VERSION 5.7 ;
  NOWIREEXTENSIONATPIN ON ;
  DIVIDERCHAR "/" ;
  BUSBITCHARS "[]" ;
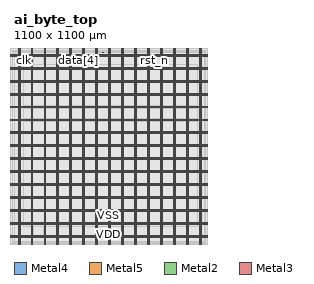
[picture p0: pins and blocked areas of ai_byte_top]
MACRO ai_byte_top
  CLASS BLOCK ;
  FOREIGN ai_byte_top ;
  ORIGIN 0.000 0.000 ;
  SIZE 1100.000 BY 1100.000 ;
  PIN VDD
    DIRECTION INOUT ;
    USE POWER ;
    PORT
      LAYER Metal4 ;
        RECT 23.900 -15.940 28.900 1117.460 ;
    END
    PORT
      LAYER Metal4 ;
        RECT 98.900 -15.940 103.900 1117.460 ;
    END
    PORT
      LAYER Metal4 ;
        RECT 173.900 -15.940 178.900 1117.460 ;
    END
    PORT
      LAYER Metal4 ;
        RECT 248.900 -15.940 253.900 1117.460 ;
    END
    PORT
      LAYER Metal4 ;
        RECT 323.900 -15.940 328.900 1117.460 ;
    END
    PORT
      LAYER Metal4 ;
        RECT 398.900 -15.940 403.900 1117.460 ;
    END
    PORT
      LAYER Metal4 ;
        RECT 473.900 -15.940 478.900 1117.460 ;
    END
    PORT
      LAYER Metal4 ;
        RECT 548.900 -15.940 553.900 1117.460 ;
    END
    PORT
      LAYER Metal4 ;
        RECT 623.900 -15.940 628.900 1117.460 ;
    END
    PORT
      LAYER Metal4 ;
        RECT 698.900 -15.940 703.900 1117.460 ;
    END
    PORT
      LAYER Metal4 ;
        RECT 773.900 -15.940 778.900 1117.460 ;
    END
    PORT
      LAYER Metal4 ;
        RECT 848.900 -15.940 853.900 1117.460 ;
    END
    PORT
      LAYER Metal4 ;
        RECT 923.900 -15.940 928.900 1117.460 ;
    END
    PORT
      LAYER Metal4 ;
        RECT 998.900 -15.940 1003.900 1117.460 ;
    END
    PORT
      LAYER Metal4 ;
        RECT 1073.900 -15.940 1078.900 1117.460 ;
    END
    PORT
      LAYER Metal5 ;
        RECT -17.620 25.910 1117.460 30.910 ;
    END
    PORT
      LAYER Metal5 ;
        RECT -17.620 100.910 1117.460 105.910 ;
    END
    PORT
      LAYER Metal5 ;
        RECT -17.620 175.910 1117.460 180.910 ;
    END
    PORT
      LAYER Metal5 ;
        RECT -17.620 250.910 1117.460 255.910 ;
    END
    PORT
      LAYER Metal5 ;
        RECT -17.620 325.910 1117.460 330.910 ;
    END
    PORT
      LAYER Metal5 ;
        RECT -17.620 400.910 1117.460 405.910 ;
    END
    PORT
      LAYER Metal5 ;
        RECT -17.620 475.910 1117.460 480.910 ;
    END
    PORT
      LAYER Metal5 ;
        RECT -17.620 550.910 1117.460 555.910 ;
    END
    PORT
      LAYER Metal5 ;
        RECT -17.620 625.910 1117.460 630.910 ;
    END
    PORT
      LAYER Metal5 ;
        RECT -17.620 700.910 1117.460 705.910 ;
    END
    PORT
      LAYER Metal5 ;
        RECT -17.620 775.910 1117.460 780.910 ;
    END
    PORT
      LAYER Metal5 ;
        RECT -17.620 850.910 1117.460 855.910 ;
    END
    PORT
      LAYER Metal5 ;
        RECT -17.620 925.910 1117.460 930.910 ;
    END
    PORT
      LAYER Metal5 ;
        RECT -17.620 1000.910 1117.460 1005.910 ;
    END
    PORT
      LAYER Metal5 ;
        RECT -17.620 1075.910 1117.460 1080.910 ;
    END
  END VDD
  PIN VSS
    DIRECTION INOUT ;
    USE GROUND ;
    PORT
      LAYER Metal4 ;
        RECT 29.900 -15.940 34.900 1117.460 ;
    END
    PORT
      LAYER Metal4 ;
        RECT 104.900 -15.940 109.900 1117.460 ;
    END
    PORT
      LAYER Metal4 ;
        RECT 179.900 -15.940 184.900 1117.460 ;
    END
    PORT
      LAYER Metal4 ;
        RECT 254.900 -15.940 259.900 1117.460 ;
    END
    PORT
      LAYER Metal4 ;
        RECT 329.900 -15.940 334.900 1117.460 ;
    END
    PORT
      LAYER Metal4 ;
        RECT 404.900 -15.940 409.900 1117.460 ;
    END
    PORT
      LAYER Metal4 ;
        RECT 479.900 -15.940 484.900 1117.460 ;
    END
    PORT
      LAYER Metal4 ;
        RECT 554.900 -15.940 559.900 1117.460 ;
    END
    PORT
      LAYER Metal4 ;
        RECT 629.900 -15.940 634.900 1117.460 ;
    END
    PORT
      LAYER Metal4 ;
        RECT 704.900 -15.940 709.900 1117.460 ;
    END
    PORT
      LAYER Metal4 ;
        RECT 779.900 -15.940 784.900 1117.460 ;
    END
    PORT
      LAYER Metal4 ;
        RECT 854.900 -15.940 859.900 1117.460 ;
    END
    PORT
      LAYER Metal4 ;
        RECT 929.900 -15.940 934.900 1117.460 ;
    END
    PORT
      LAYER Metal4 ;
        RECT 1004.900 -15.940 1009.900 1117.460 ;
    END
    PORT
      LAYER Metal4 ;
        RECT 1079.900 -15.940 1084.900 1117.460 ;
    END
    PORT
      LAYER Metal5 ;
        RECT -17.620 31.910 1117.460 36.910 ;
    END
    PORT
      LAYER Metal5 ;
        RECT -17.620 106.910 1117.460 111.910 ;
    END
    PORT
      LAYER Metal5 ;
        RECT -17.620 181.910 1117.460 186.910 ;
    END
    PORT
      LAYER Metal5 ;
        RECT -17.620 256.910 1117.460 261.910 ;
    END
    PORT
      LAYER Metal5 ;
        RECT -17.620 331.910 1117.460 336.910 ;
    END
    PORT
      LAYER Metal5 ;
        RECT -17.620 406.910 1117.460 411.910 ;
    END
    PORT
      LAYER Metal5 ;
        RECT -17.620 481.910 1117.460 486.910 ;
    END
    PORT
      LAYER Metal5 ;
        RECT -17.620 556.910 1117.460 561.910 ;
    END
    PORT
      LAYER Metal5 ;
        RECT -17.620 631.910 1117.460 636.910 ;
    END
    PORT
      LAYER Metal5 ;
        RECT -17.620 706.910 1117.460 711.910 ;
    END
    PORT
      LAYER Metal5 ;
        RECT -17.620 781.910 1117.460 786.910 ;
    END
    PORT
      LAYER Metal5 ;
        RECT -17.620 856.910 1117.460 861.910 ;
    END
    PORT
      LAYER Metal5 ;
        RECT -17.620 931.910 1117.460 936.910 ;
    END
    PORT
      LAYER Metal5 ;
        RECT -17.620 1006.910 1117.460 1011.910 ;
    END
    PORT
      LAYER Metal5 ;
        RECT -17.620 1081.910 1117.460 1086.910 ;
    END
  END VSS
  PIN addr[0]
    DIRECTION INPUT ;
    USE SIGNAL ;
    ANTENNAGATEAREA 0.396000 ;
    PORT
      LAYER Metal2 ;
        RECT 427.840 1099.440 428.400 1100.000 ;
    END
  END addr[0]
  PIN addr[1]
    DIRECTION INPUT ;
    USE SIGNAL ;
    ANTENNAGATEAREA 0.396000 ;
    PORT
      LAYER Metal2 ;
        RECT 430.080 1099.440 430.640 1100.000 ;
    END
  END addr[1]
  PIN addr[2]
    DIRECTION INPUT ;
    USE SIGNAL ;
    ANTENNAGATEAREA 0.396000 ;
    PORT
      LAYER Metal2 ;
        RECT 448.000 1099.440 448.560 1100.000 ;
    END
  END addr[2]
  PIN addr[3]
    DIRECTION INPUT ;
    USE SIGNAL ;
    ANTENNAGATEAREA 0.396000 ;
    PORT
      LAYER Metal2 ;
        RECT 450.240 1099.440 450.800 1100.000 ;
    END
  END addr[3]
  PIN clk
    DIRECTION INPUT ;
    USE SIGNAL ;
    ANTENNAGATEAREA 4.738000 ;
    PORT
      LAYER Metal3 ;
        RECT 0.000 1083.040 0.560 1083.600 ;
    END
  END clk
  PIN data[0]
    DIRECTION INOUT ;
    USE SIGNAL ;
    PORT
      LAYER Metal2 ;
        RECT 376.320 1099.440 376.880 1100.000 ;
    END
  END data[0]
  PIN data[1]
    DIRECTION INOUT ;
    USE SIGNAL ;
    ANTENNAGATEAREA 0.396000 ;
    ANTENNADIFFAREA 2.080400 ;
    PORT
      LAYER Metal2 ;
        RECT 393.120 1099.440 393.680 1100.000 ;
    END
  END data[1]
  PIN data[2]
    DIRECTION INOUT ;
    USE SIGNAL ;
    PORT
      LAYER Metal2 ;
        RECT 395.360 1099.440 395.920 1100.000 ;
    END
  END data[2]
  PIN data[3]
    DIRECTION INOUT ;
    USE SIGNAL ;
    ANTENNAGATEAREA 1.057000 ;
    ANTENNADIFFAREA 2.080400 ;
    PORT
      LAYER Metal2 ;
        RECT 396.480 1099.440 397.040 1100.000 ;
    END
  END data[3]
  PIN data[4]
    DIRECTION INOUT ;
    USE SIGNAL ;
    ANTENNADIFFAREA 1.986000 ;
    PORT
      LAYER Metal2 ;
        RECT 370.720 1099.440 371.280 1100.000 ;
    END
  END data[4]
  PIN data[5]
    DIRECTION INOUT ;
    USE SIGNAL ;
    ANTENNAGATEAREA 1.057000 ;
    ANTENNADIFFAREA 0.897600 ;
    PORT
      LAYER Metal2 ;
        RECT 336.000 1099.440 336.560 1100.000 ;
    END
  END data[5]
  PIN data[6]
    DIRECTION INOUT ;
    USE SIGNAL ;
    ANTENNAGATEAREA 1.057000 ;
    ANTENNADIFFAREA 0.897600 ;
    PORT
      LAYER Metal2 ;
        RECT 343.840 1099.440 344.400 1100.000 ;
    END
  END data[6]
  PIN data[7]
    DIRECTION INOUT ;
    USE SIGNAL ;
    ANTENNAGATEAREA 0.396000 ;
    ANTENNADIFFAREA 0.897600 ;
    PORT
      LAYER Metal2 ;
        RECT 329.280 1099.440 329.840 1100.000 ;
    END
  END data[7]
  PIN debug_state[0]
    DIRECTION OUTPUT ;
    USE SIGNAL ;
    ANTENNADIFFAREA 0.897600 ;
    PORT
      LAYER Metal2 ;
        RECT 515.200 1099.440 515.760 1100.000 ;
    END
  END debug_state[0]
  PIN debug_state[1]
    DIRECTION OUTPUT ;
    USE SIGNAL ;
    ANTENNADIFFAREA 0.897600 ;
    PORT
      LAYER Metal2 ;
        RECT 529.760 1099.440 530.320 1100.000 ;
    END
  END debug_state[1]
  PIN debug_state[2]
    DIRECTION OUTPUT ;
    USE SIGNAL ;
    ANTENNADIFFAREA 0.897600 ;
    PORT
      LAYER Metal2 ;
        RECT 528.640 1099.440 529.200 1100.000 ;
    END
  END debug_state[2]
  PIN done_o
    DIRECTION OUTPUT ;
    USE SIGNAL ;
    ANTENNADIFFAREA 0.897600 ;
    PORT
      LAYER Metal2 ;
        RECT 514.080 1099.440 514.640 1100.000 ;
    END
  END done_o
  PIN error_o
    DIRECTION OUTPUT ;
    USE SIGNAL ;
    ANTENNADIFFAREA 0.897600 ;
    PORT
      LAYER Metal2 ;
        RECT 499.520 1099.440 500.080 1100.000 ;
    END
  END error_o
  PIN irq
    DIRECTION OUTPUT ;
    USE SIGNAL ;
    ANTENNADIFFAREA 0.897600 ;
    PORT
      LAYER Metal2 ;
        RECT 484.960 1099.440 485.520 1100.000 ;
    END
  END irq
  PIN re
    DIRECTION INPUT ;
    USE SIGNAL ;
    ANTENNAGATEAREA 0.396000 ;
    PORT
      LAYER Metal2 ;
        RECT 512.960 1099.440 513.520 1100.000 ;
    END
  END re
  PIN rst_n
    DIRECTION INPUT ;
    USE SIGNAL ;
    ANTENNAGATEAREA 0.396000 ;
    PORT
      LAYER Metal2 ;
        RECT 815.360 1099.440 815.920 1100.000 ;
    END
  END rst_n
  PIN we
    DIRECTION INPUT ;
    USE SIGNAL ;
    ANTENNAGATEAREA 0.396000 ;
    PORT
      LAYER Metal2 ;
        RECT 549.920 1099.440 550.480 1100.000 ;
    END
  END we
  OBS
      LAYER Nwell ;
        RECT 9.650 11.330 1090.190 1094.110 ;
      LAYER Metal1 ;
        RECT 10.080 11.460 1089.760 1093.980 ;
      LAYER Metal2 ;
        RECT -17.620 -15.940 -7.620 1117.460 ;
        RECT -5.920 1100.000 4.080 1105.760 ;
        RECT 1095.760 1100.000 1105.760 1105.760 ;
        RECT -5.920 1099.140 328.980 1100.000 ;
        RECT 330.140 1099.140 335.700 1100.000 ;
        RECT 336.860 1099.140 343.540 1100.000 ;
        RECT 344.700 1099.140 370.420 1100.000 ;
        RECT 371.580 1099.140 376.020 1100.000 ;
        RECT 377.180 1099.140 392.820 1100.000 ;
        RECT 393.980 1099.140 395.060 1100.000 ;
        RECT 397.340 1099.140 427.540 1100.000 ;
        RECT 428.700 1099.140 429.780 1100.000 ;
        RECT 430.940 1099.140 447.700 1100.000 ;
        RECT 448.860 1099.140 449.940 1100.000 ;
        RECT 451.100 1099.140 484.660 1100.000 ;
        RECT 485.820 1099.140 499.220 1100.000 ;
        RECT 500.380 1099.140 512.660 1100.000 ;
        RECT 516.060 1099.140 528.340 1100.000 ;
        RECT 530.620 1099.140 549.620 1100.000 ;
        RECT 550.780 1099.140 815.060 1100.000 ;
        RECT 816.220 1099.140 1105.760 1100.000 ;
        RECT -5.920 0.000 1105.760 1099.140 ;
        RECT -5.920 -4.240 4.080 0.000 ;
        RECT 1095.760 -4.240 1105.760 0.000 ;
        RECT 1107.460 -15.940 1117.460 1117.460 ;
      LAYER Metal3 ;
        RECT -17.620 1107.460 1117.460 1117.460 ;
        RECT -5.920 1095.760 1105.760 1105.760 ;
        RECT -17.460 1082.100 -7.780 1086.720 ;
        RECT 0.000 1083.900 1100.000 1095.760 ;
        RECT 0.860 1082.740 1100.000 1083.900 ;
        RECT 0.000 1080.720 1100.000 1082.740 ;
        RECT 1107.620 1082.100 1117.300 1086.720 ;
        RECT -5.760 1076.100 1105.600 1080.720 ;
        RECT -17.460 1007.100 -7.780 1011.720 ;
        RECT 0.000 1005.720 1100.000 1076.100 ;
        RECT 1107.620 1007.100 1117.300 1011.720 ;
        RECT -5.760 1001.100 1105.600 1005.720 ;
        RECT -17.460 932.100 -7.780 936.720 ;
        RECT 0.000 930.720 1100.000 1001.100 ;
        RECT 1107.620 932.100 1117.300 936.720 ;
        RECT -5.760 926.100 1105.600 930.720 ;
        RECT -17.460 857.100 -7.780 861.720 ;
        RECT 0.000 855.720 1100.000 926.100 ;
        RECT 1107.620 857.100 1117.300 861.720 ;
        RECT -5.760 851.100 1105.600 855.720 ;
        RECT -17.460 782.100 -7.780 786.720 ;
        RECT 0.000 780.720 1100.000 851.100 ;
        RECT 1107.620 782.100 1117.300 786.720 ;
        RECT -5.760 776.100 1105.600 780.720 ;
        RECT -17.460 707.100 -7.780 711.720 ;
        RECT 0.000 705.720 1100.000 776.100 ;
        RECT 1107.620 707.100 1117.300 711.720 ;
        RECT -5.760 701.100 1105.600 705.720 ;
        RECT -17.460 632.100 -7.780 636.720 ;
        RECT 0.000 630.720 1100.000 701.100 ;
        RECT 1107.620 632.100 1117.300 636.720 ;
        RECT -5.760 626.100 1105.600 630.720 ;
        RECT -17.460 557.100 -7.780 561.720 ;
        RECT 0.000 555.720 1100.000 626.100 ;
        RECT 1107.620 557.100 1117.300 561.720 ;
        RECT -5.760 551.100 1105.600 555.720 ;
        RECT -17.460 482.100 -7.780 486.720 ;
        RECT 0.000 480.720 1100.000 551.100 ;
        RECT 1107.620 482.100 1117.300 486.720 ;
        RECT -5.760 476.100 1105.600 480.720 ;
        RECT -17.460 407.100 -7.780 411.720 ;
        RECT 0.000 405.720 1100.000 476.100 ;
        RECT 1107.620 407.100 1117.300 411.720 ;
        RECT -5.760 401.100 1105.600 405.720 ;
        RECT -17.460 332.100 -7.780 336.720 ;
        RECT 0.000 330.720 1100.000 401.100 ;
        RECT 1107.620 332.100 1117.300 336.720 ;
        RECT -5.760 326.100 1105.600 330.720 ;
        RECT -17.460 257.100 -7.780 261.720 ;
        RECT 0.000 255.720 1100.000 326.100 ;
        RECT 1107.620 257.100 1117.300 261.720 ;
        RECT -5.760 251.100 1105.600 255.720 ;
        RECT -17.460 182.100 -7.780 186.720 ;
        RECT 0.000 180.720 1100.000 251.100 ;
        RECT 1107.620 182.100 1117.300 186.720 ;
        RECT -5.760 176.100 1105.600 180.720 ;
        RECT -17.460 107.100 -7.780 111.720 ;
        RECT 0.000 105.720 1100.000 176.100 ;
        RECT 1107.620 107.100 1117.300 111.720 ;
        RECT -5.760 101.100 1105.600 105.720 ;
        RECT -17.460 32.100 -7.780 36.720 ;
        RECT 0.000 30.720 1100.000 101.100 ;
        RECT 1107.620 32.100 1117.300 36.720 ;
        RECT -5.760 26.100 1105.600 30.720 ;
        RECT 0.000 5.760 1100.000 26.100 ;
        RECT -5.920 -4.240 1105.760 5.760 ;
        RECT -17.620 -15.940 1117.460 -5.940 ;
      LAYER Metal4 ;
        RECT -17.410 1082.050 -7.830 1086.770 ;
        RECT 0.000 1080.770 23.600 1086.770 ;
        RECT -5.710 1076.050 23.600 1080.770 ;
        RECT -17.410 1007.050 -7.830 1011.770 ;
        RECT 0.000 1005.770 23.600 1076.050 ;
        RECT -5.710 1001.050 23.600 1005.770 ;
        RECT -17.410 932.050 -7.830 936.770 ;
        RECT 0.000 930.770 23.600 1001.050 ;
        RECT -5.710 926.050 23.600 930.770 ;
        RECT -17.410 857.050 -7.830 861.770 ;
        RECT 0.000 855.770 23.600 926.050 ;
        RECT -5.710 851.050 23.600 855.770 ;
        RECT -17.410 782.050 -7.830 786.770 ;
        RECT 0.000 780.770 23.600 851.050 ;
        RECT -5.710 776.050 23.600 780.770 ;
        RECT -17.410 707.050 -7.830 711.770 ;
        RECT 0.000 705.770 23.600 776.050 ;
        RECT -5.710 701.050 23.600 705.770 ;
        RECT -17.410 632.050 -7.830 636.770 ;
        RECT 0.000 630.770 23.600 701.050 ;
        RECT -5.710 626.050 23.600 630.770 ;
        RECT -17.410 557.050 -7.830 561.770 ;
        RECT 0.000 555.770 23.600 626.050 ;
        RECT -5.710 551.050 23.600 555.770 ;
        RECT -17.410 482.050 -7.830 486.770 ;
        RECT 0.000 480.770 23.600 551.050 ;
        RECT -5.710 476.050 23.600 480.770 ;
        RECT -17.410 407.050 -7.830 411.770 ;
        RECT 0.000 405.770 23.600 476.050 ;
        RECT -5.710 401.050 23.600 405.770 ;
        RECT -17.410 332.050 -7.830 336.770 ;
        RECT 0.000 330.770 23.600 401.050 ;
        RECT -5.710 326.050 23.600 330.770 ;
        RECT -17.410 257.050 -7.830 261.770 ;
        RECT 0.000 255.770 23.600 326.050 ;
        RECT -5.710 251.050 23.600 255.770 ;
        RECT -17.410 182.050 -7.830 186.770 ;
        RECT 0.000 180.770 23.600 251.050 ;
        RECT -5.710 176.050 23.600 180.770 ;
        RECT -17.410 107.050 -7.830 111.770 ;
        RECT 0.000 105.770 23.600 176.050 ;
        RECT -5.710 101.050 23.600 105.770 ;
        RECT -17.410 32.050 -7.830 36.770 ;
        RECT 0.000 30.770 23.600 101.050 ;
        RECT -5.710 26.050 23.600 30.770 ;
        RECT 0.000 25.290 23.600 26.050 ;
        RECT 29.200 25.290 29.600 1086.770 ;
        RECT 35.200 25.290 98.600 1086.770 ;
        RECT 104.200 25.290 104.600 1086.770 ;
        RECT 110.200 25.290 173.600 1086.770 ;
        RECT 179.200 25.290 179.600 1086.770 ;
        RECT 185.200 25.290 248.600 1086.770 ;
        RECT 254.200 25.290 254.600 1086.770 ;
        RECT 260.200 25.290 323.600 1086.770 ;
        RECT 329.200 25.290 329.600 1086.770 ;
        RECT 335.200 25.290 398.600 1086.770 ;
        RECT 404.200 25.290 404.600 1086.770 ;
        RECT 410.200 25.290 473.600 1086.770 ;
        RECT 479.200 25.290 479.600 1086.770 ;
        RECT 485.200 25.290 548.600 1086.770 ;
        RECT 554.200 25.290 554.600 1086.770 ;
        RECT 560.200 25.290 623.600 1086.770 ;
        RECT 629.200 25.290 629.600 1086.770 ;
        RECT 635.200 25.290 698.600 1086.770 ;
        RECT 704.200 25.290 704.600 1086.770 ;
        RECT 710.200 25.290 773.600 1086.770 ;
        RECT 779.200 25.290 779.600 1086.770 ;
        RECT 785.200 25.290 848.600 1086.770 ;
        RECT 854.200 25.290 854.600 1086.770 ;
        RECT 860.200 25.290 923.600 1086.770 ;
        RECT 929.200 25.290 929.600 1086.770 ;
        RECT 935.200 25.290 998.600 1086.770 ;
        RECT 1004.200 25.290 1004.600 1086.770 ;
        RECT 1010.200 25.290 1073.600 1086.770 ;
        RECT 1079.200 25.290 1079.600 1086.770 ;
        RECT 1085.200 1080.770 1100.000 1086.770 ;
        RECT 1107.670 1082.050 1117.250 1086.770 ;
        RECT 1085.200 1076.050 1105.550 1080.770 ;
        RECT 1085.200 1005.770 1100.000 1076.050 ;
        RECT 1107.670 1007.050 1117.250 1011.770 ;
        RECT 1085.200 1001.050 1105.550 1005.770 ;
        RECT 1085.200 930.770 1100.000 1001.050 ;
        RECT 1107.670 932.050 1117.250 936.770 ;
        RECT 1085.200 926.050 1105.550 930.770 ;
        RECT 1085.200 855.770 1100.000 926.050 ;
        RECT 1107.670 857.050 1117.250 861.770 ;
        RECT 1085.200 851.050 1105.550 855.770 ;
        RECT 1085.200 780.770 1100.000 851.050 ;
        RECT 1107.670 782.050 1117.250 786.770 ;
        RECT 1085.200 776.050 1105.550 780.770 ;
        RECT 1085.200 705.770 1100.000 776.050 ;
        RECT 1107.670 707.050 1117.250 711.770 ;
        RECT 1085.200 701.050 1105.550 705.770 ;
        RECT 1085.200 630.770 1100.000 701.050 ;
        RECT 1107.670 632.050 1117.250 636.770 ;
        RECT 1085.200 626.050 1105.550 630.770 ;
        RECT 1085.200 555.770 1100.000 626.050 ;
        RECT 1107.670 557.050 1117.250 561.770 ;
        RECT 1085.200 551.050 1105.550 555.770 ;
        RECT 1085.200 480.770 1100.000 551.050 ;
        RECT 1107.670 482.050 1117.250 486.770 ;
        RECT 1085.200 476.050 1105.550 480.770 ;
        RECT 1085.200 405.770 1100.000 476.050 ;
        RECT 1107.670 407.050 1117.250 411.770 ;
        RECT 1085.200 401.050 1105.550 405.770 ;
        RECT 1085.200 330.770 1100.000 401.050 ;
        RECT 1107.670 332.050 1117.250 336.770 ;
        RECT 1085.200 326.050 1105.550 330.770 ;
        RECT 1085.200 255.770 1100.000 326.050 ;
        RECT 1107.670 257.050 1117.250 261.770 ;
        RECT 1085.200 251.050 1105.550 255.770 ;
        RECT 1085.200 180.770 1100.000 251.050 ;
        RECT 1107.670 182.050 1117.250 186.770 ;
        RECT 1085.200 176.050 1105.550 180.770 ;
        RECT 1085.200 105.770 1100.000 176.050 ;
        RECT 1107.670 107.050 1117.250 111.770 ;
        RECT 1085.200 101.050 1105.550 105.770 ;
        RECT 1085.200 30.770 1100.000 101.050 ;
        RECT 1107.670 32.050 1117.250 36.770 ;
        RECT 1085.200 26.050 1105.550 30.770 ;
        RECT 1085.200 25.290 1100.000 26.050 ;
      LAYER Metal5 ;
        RECT 57.740 1012.510 1065.060 1024.870 ;
        RECT 57.740 937.510 1065.060 1000.310 ;
        RECT 57.740 862.510 1065.060 925.310 ;
        RECT 57.740 787.510 1065.060 850.310 ;
        RECT 57.740 712.510 1065.060 775.310 ;
        RECT 57.740 637.510 1065.060 700.310 ;
        RECT 57.740 562.510 1065.060 625.310 ;
        RECT 57.740 487.510 1065.060 550.310 ;
        RECT 57.740 412.510 1065.060 475.310 ;
        RECT 57.740 337.510 1065.060 400.310 ;
        RECT 57.740 262.510 1065.060 325.310 ;
        RECT 57.740 187.510 1065.060 250.310 ;
        RECT 57.740 112.510 1065.060 175.310 ;
        RECT 57.740 87.530 1065.060 100.310 ;
  END
END ai_byte_top
END LIBRARY

